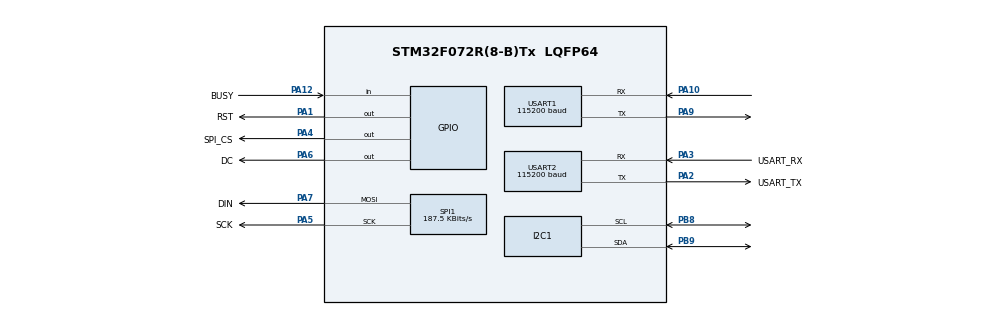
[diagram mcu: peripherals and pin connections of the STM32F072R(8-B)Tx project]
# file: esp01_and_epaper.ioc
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Dma.Request0=USART1_RX
Dma.USART1_RX.0.Direction=DMA_PERIPH_TO_MEMORY
Dma.USART1_RX.0.Instance=DMA1_Channel3
Dma.USART1_RX.0.MemDataAlignment=DMA_MDATAALIGN_BYTE
Dma.USART1_RX.0.MemInc=DMA_MINC_ENABLE
Dma.USART1_RX.0.Mode=DMA_CIRCULAR
Dma.USART1_RX.0.PeriphDataAlignment=DMA_PDATAALIGN_BYTE
Dma.USART1_RX.0.PeriphInc=DMA_PINC_DISABLE
Dma.USART1_RX.0.Priority=DMA_PRIORITY_LOW
I2C1.Timing=0x00201D2B
Mcu.Family=STM32F0
Mcu.Name=STM32F072R(8-B)Tx
Mcu.Package=LQFP64
NVIC.DMA1_Channel2_3_IRQn=true\:0\:0\:false\:false\:true\:false\:true\:true
NVIC.TIM3_IRQn=true\:0\:0\:false\:false\:true\:true\:true\:true
PA1.GPIO_Label=RST
PA1.Signal=GPIO_Output
PA10.Mode=Asynchronous
PA10.Signal=USART1_RX
PA12.GPIO_Label=BUSY
PA12.Signal=GPIO_Input
PA2.GPIO_Label=USART_TX
PA2.GPIO_Mode=GPIO_MODE_AF_PP
PA2.GPIO_PuPd=GPIO_NOPULL
PA2.GPIO_Speed=GPIO_SPEED_FREQ_LOW
PA2.Mode=Asynchronous
PA2.Signal=USART2_TX
PA3.GPIO_Label=USART_RX
PA3.GPIO_Mode=GPIO_MODE_AF_PP
PA3.GPIO_PuPd=GPIO_NOPULL
PA3.GPIO_Speed=GPIO_SPEED_FREQ_LOW
PA3.Mode=Asynchronous
PA3.Signal=USART2_RX
PA4.GPIO_Label=SPI_CS
PA4.Signal=GPIO_Output
PA5.GPIO_Label=SCK
PA5.Mode=TX_Only_Simplex_Unidirect_Master
PA5.Signal=SPI1_SCK
PA6.GPIO_Label=DC
PA6.Signal=GPIO_Output
PA7.GPIO_Label=DIN
PA7.Mode=TX_Only_Simplex_Unidirect_Master
PA7.Signal=SPI1_MOSI
PA9.Mode=Asynchronous
PA9.Signal=USART1_TX
PB8.GPIO_Pu=GPIO_PULLUP
PB8.Mode=I2C
PB8.Signal=I2C1_SCL
PB9.GPIO_Pu=GPIO_PULLUP
PB9.Mode=I2C
PB9.Signal=I2C1_SDA
ProjectManager.HeapSize=0x200
ProjectManager.StackSize=0x400
ProjectManager.TargetToolchain=STM32CubeIDE
RCC.AHBFreq_Value=48000000
RCC.APB1Freq_Value=48000000
RCC.APB1TimFreq_Value=48000000
RCC.FLatency-AdvancedSettings=FLASH_LATENCY_1
RCC.HCLKFreq_Value=48000000
RCC.PLLDivider=RCC_PREDIV_DIV2
RCC.PLLMUL=RCC_PLL_MUL12
RCC.PREFETCH_ENABLE-AdvancedSettings=1
RCC.SYSCLKFreq_VALUE=48000000
RCC.SYSCLKSource=RCC_SYSCLKSOURCE_HSI48
SPI1.BaudRatePrescaler=SPI_BAUDRATEPRESCALER_256
SPI1.CalculateBaudRate=187.5 KBits/s
SPI1.DataSize=SPI_DATASIZE_8BIT
SPI1.Direction=SPI_DIRECTION_2LINES
SPI1.Mode=SPI_MODE_MASTER
SPI1.VirtualType=VM_MASTER
TIM3.Period=59999
TIM3.Prescaler=47999
USART1.BaudRate=115200
USART1.VirtualMode-Asynchronous=VM_ASYNC
USART2.BaudRate=115200
USART2.VirtualMode=VM_ASYNC
USART2.VirtualMode-Asynchronous=VM_ASYNC
VP_TIM3_VS_ClockSourceINT.Mode=Internal
board=NUCLEO-F072RB

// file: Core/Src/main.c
/* USER CODE BEGIN Header */
/**
  ******************************************************************************
  * @file           : main.c
  * @brief          : Main program body
  ******************************************************************************
  * @attention
  *
  * Copyright (c) 2026 STMicroelectronics.
  * All rights reserved.
  *
  * This software is licensed under terms that can be found in the LICENSE file
  * in the root directory of this software component.
  * If no LICENSE file comes with this software, it is provided AS-IS.
  *
  ******************************************************************************
  */
/* USER CODE END Header */
#include "main.h"

/* USER CODE BEGIN Includes */

#include <stdio.h>
#include <stdlib.h> // malloc() free()
#include <string.h>
#include "ESP01_HAL.h"
#include "date_converter.h"
#include "DRIVER.h"
#include "EPAPER.h"
#include "bme280.h"

/* USER CODE END Includes */

I2C_HandleTypeDef hi2c1;

SPI_HandleTypeDef hspi1;

TIM_HandleTypeDef htim3;

UART_HandleTypeDef huart1;
UART_HandleTypeDef huart2;
DMA_HandleTypeDef hdma_usart1_rx;

/* USER CODE BEGIN PV */
uint8_t dma_rx_buf[1024]; // Buffer DMA pour la réception ESP01
/* USER CODE END PV */

void SystemClock_Config(void);
static void MX_GPIO_Init(void);
static void MX_DMA_Init(void);
static void MX_USART2_UART_Init(void);
static void MX_USART1_UART_Init(void);
static void MX_SPI1_Init(void);
static void MX_TIM3_Init(void);
static void MX_I2C1_Init(void);

/* USER CODE BEGIN 0 */
uint8_t day = 0;
uint8_t prev_day = 0;
uint8_t dd = 0;
uint8_t mm = 0;
uint16_t yy = 0;
uint16_t minute = 0;
uint16_t prev_minute = 0;
uint8_t moon_phase = 0;

int temp = 0;
int prev_temp = 0;
uint32_t press = 0;
uint32_t prev_press = 0;
uint32_t hum = 0;
uint32_t prev_hum = 0;

uint8_t wifi_update_done = 0;
/* USER CODE END 0 */

int main(void)
{

  /* MCU Configuration--------------------------------------------------------*/

  /* Reset of all peripherals, Initializes the Flash interface and the Systick. */
  HAL_Init();

  /* Configure the system clock */
  SystemClock_Config();

  /* Initialize all configured peripherals */
  MX_GPIO_Init();
  MX_DMA_Init();
  MX_USART2_UART_Init();
  MX_USART1_UART_Init();
  MX_SPI1_Init();
  MX_TIM3_Init();
  MX_I2C1_Init();
  /* USER CODE BEGIN 2 */

  if (HAL_TIM_Base_Start_IT(&htim3) != HAL_OK)
  {
    /* Starting Error */
    Error_Handler();
  }
  BME_Init();
  BME_Read_Data(&temp, &press, &hum);

  Init_Wifi("Wifi_name", "Wifi_pswd");
  if(Get_Date(&day, &dd, &mm, &yy, &minute) == 0){
	UTC_to_Paris(&day, &dd, &mm, &yy, &minute);
  }
  prev_minute = minute + 1111;

  moon_phase = Moon_Phase(dd,mm,yy);

  EPAPER_Init();
  EPAPER_Clear();
  HAL_Delay(500);
  EPAPER_Part_Init();
  EPAPER_KW_White_Display();
  HAL_Delay(500);

  EPAPER_Print_temp(temp);
  EPAPER_Print_press(press);
  EPAPER_Print_hum(hum);
  EPAPER_Print_Date(day,  dd, mm);
  EPAPER_Print_Hour(minute,  prev_minute);
  EPAPER_Print_Moon_Phase(moon_phase, minute, 360, 1080);

  prev_minute = minute;
  prev_day = day;
  prev_temp = temp;
  prev_hum = hum;
  prev_press = press;
  /* USER CODE END 2 */

  /* Infinite loop */
  /* USER CODE BEGIN WHILE */
  while (1)
  {

	if(prev_minute != minute)
	{
		if(minute >= 1440){
			minute = 0;
			day++;
		}

		EPAPER_Print_Hour(minute,  prev_minute);
		EPAPER_Print_Moon_Phase(moon_phase, minute, 360, 1080);
		prev_minute = minute;

		/* update temp hum and press each minute */
		BME_Read_Data(&temp, &press, &hum);

		if(prev_temp != temp){
			prev_temp = temp;
			EPAPER_Print_temp(temp);
		}
		if(prev_press != press){
			prev_press = press;
			EPAPER_Print_press(press);
		}
		if(prev_hum != hum){
			prev_hum = hum;
			EPAPER_Print_hum(hum);
		}
	}

	if(prev_day != day)
	{
		if(day >= 7){
			day = 0;
		}
		prev_day = day;

		next_day(&dd,&mm,&yy);

		EPAPER_Print_Date(day,  dd, mm);
		moon_phase = Moon_Phase(dd,mm,yy);
	}

	/* reset screen every day at 4h*/
	if((minute == 240 || minute == 600 || minute == 960 || minute == 1320) && !wifi_update_done){
		wifi_update_done = 1;

		Init_Wifi("Wifi_name", "Wifi_pswd");
		if(Get_Date(&day, &dd, &mm, &yy, &minute) == 0){
			UTC_to_Paris(&day, &dd, &mm, &yy, &minute);
		}
		prev_minute = minute + 1111;

		EPAPER_Init();
		EPAPER_Clear();
		HAL_Delay(500);
		EPAPER_Part_Init();
		EPAPER_KW_White_Display();
		HAL_Delay(500);

		EPAPER_Print_temp(temp);
		EPAPER_Print_press(press);
		EPAPER_Print_hum(hum);
		EPAPER_Print_Date(day,  dd, mm);
		EPAPER_Print_Hour(minute,  prev_minute);
		EPAPER_Print_Moon_Phase(moon_phase, minute, 360, 1080);
		prev_minute = minute;
		prev_day = day;
		prev_temp = temp;
		prev_hum = hum;
		prev_press = press;
	}

	if(minute == 241 || minute == 601 || minute == 961 || minute == 1321){
		wifi_update_done = 0;
	}
    /* USER CODE END WHILE */

  }
}

void SystemClock_Config(void)
{
  RCC_OscInitTypeDef RCC_OscInitStruct = {0};
  RCC_ClkInitTypeDef RCC_ClkInitStruct = {0};
  RCC_PeriphCLKInitTypeDef PeriphClkInit = {0};

  /** Initializes the RCC Oscillators according to the specified parameters
  * in the RCC_OscInitTypeDef structure.
  */
  RCC_OscInitStruct.OscillatorType = RCC_OSCILLATORTYPE_HSI|RCC_OSCILLATORTYPE_HSE;
  RCC_OscInitStruct.HSEState = RCC_HSE_ON;
  RCC_OscInitStruct.HSIState = RCC_HSI_ON;
  RCC_OscInitStruct.HSICalibrationValue = RCC_HSICALIBRATION_DEFAULT;
  RCC_OscInitStruct.PLL.PLLState = RCC_PLL_ON;
  RCC_OscInitStruct.PLL.PLLSource = RCC_PLLSOURCE_HSE;
  RCC_OscInitStruct.PLL.PLLMUL = RCC_PLL_MUL12;
  RCC_OscInitStruct.PLL.PREDIV = RCC_PREDIV_DIV2;
  if (HAL_RCC_OscConfig(&RCC_OscInitStruct) != HAL_OK)
  {
    Error_Handler();
  }

  /** Initializes the CPU, AHB and APB buses clocks
  */
  RCC_ClkInitStruct.ClockType = RCC_CLOCKTYPE_HCLK|RCC_CLOCKTYPE_SYSCLK
                              |RCC_CLOCKTYPE_PCLK1;
  RCC_ClkInitStruct.SYSCLKSource = RCC_SYSCLKSOURCE_PLLCLK;
  RCC_ClkInitStruct.AHBCLKDivider = RCC_SYSCLK_DIV1;
  RCC_ClkInitStruct.APB1CLKDivider = RCC_HCLK_DIV1;

  if (HAL_RCC_ClockConfig(&RCC_ClkInitStruct, FLASH_LATENCY_1) != HAL_OK)
  {
    Error_Handler();
  }
  PeriphClkInit.PeriphClockSelection = RCC_PERIPHCLK_USART1|RCC_PERIPHCLK_USART2
                              |RCC_PERIPHCLK_I2C1;
  PeriphClkInit.Usart1ClockSelection = RCC_USART1CLKSOURCE_PCLK1;
  PeriphClkInit.Usart2ClockSelection = RCC_USART2CLKSOURCE_PCLK1;
  PeriphClkInit.I2c1ClockSelection = RCC_I2C1CLKSOURCE_HSI;
  if (HAL_RCCEx_PeriphCLKConfig(&PeriphClkInit) != HAL_OK)
  {
    Error_Handler();
  }
}

static void MX_I2C1_Init(void)
{

  hi2c1.Instance = I2C1;
  hi2c1.Init.Timing = 0x00201D2B;
  hi2c1.Init.OwnAddress1 = 0;
  hi2c1.Init.AddressingMode = I2C_ADDRESSINGMODE_7BIT;
  hi2c1.Init.DualAddressMode = I2C_DUALADDRESS_DISABLE;
  hi2c1.Init.OwnAddress2 = 0;
  hi2c1.Init.OwnAddress2Masks = I2C_OA2_NOMASK;
  hi2c1.Init.GeneralCallMode = I2C_GENERALCALL_DISABLE;
  hi2c1.Init.NoStretchMode = I2C_NOSTRETCH_DISABLE;
  if (HAL_I2C_Init(&hi2c1) != HAL_OK)
  {
    Error_Handler();
  }

  /** Configure Analogue filter
  */
  if (HAL_I2CEx_ConfigAnalogFilter(&hi2c1, I2C_ANALOGFILTER_ENABLE) != HAL_OK)
  {
    Error_Handler();
  }

  /** Configure Digital filter
  */
  if (HAL_I2CEx_ConfigDigitalFilter(&hi2c1, 0) != HAL_OK)
  {
    Error_Handler();
  }

}

static void MX_SPI1_Init(void)
{

  /* SPI1 parameter configuration*/
  hspi1.Instance = SPI1;
  hspi1.Init.Mode = SPI_MODE_MASTER;
  hspi1.Init.Direction = SPI_DIRECTION_2LINES;
  hspi1.Init.DataSize = SPI_DATASIZE_8BIT;
  hspi1.Init.CLKPolarity = SPI_POLARITY_LOW;
  hspi1.Init.CLKPhase = SPI_PHASE_1EDGE;
  hspi1.Init.NSS = SPI_NSS_SOFT;
  hspi1.Init.BaudRatePrescaler = SPI_BAUDRATEPRESCALER_256;
  hspi1.Init.FirstBit = SPI_FIRSTBIT_MSB;
  hspi1.Init.TIMode = SPI_TIMODE_DISABLE;
  hspi1.Init.CRCCalculation = SPI_CRCCALCULATION_DISABLE;
  hspi1.Init.CRCPolynomial = 7;
  hspi1.Init.CRCLength = SPI_CRC_LENGTH_DATASIZE;
  hspi1.Init.NSSPMode = SPI_NSS_PULSE_ENABLE;
  if (HAL_SPI_Init(&hspi1) != HAL_OK)
  {
    Error_Handler();
  }

}

static void MX_TIM3_Init(void)
{

  TIM_ClockConfigTypeDef sClockSourceConfig = {0};
  TIM_MasterConfigTypeDef sMasterConfig = {0};

  htim3.Instance = TIM3;
  htim3.Init.Prescaler = 47999;
  htim3.Init.CounterMode = TIM_COUNTERMODE_UP;
  htim3.Init.Period = 59999;
  htim3.Init.ClockDivision = TIM_CLOCKDIVISION_DIV1;
  htim3.Init.AutoReloadPreload = TIM_AUTORELOAD_PRELOAD_DISABLE;
  if (HAL_TIM_Base_Init(&htim3) != HAL_OK)
  {
    Error_Handler();
  }
  sClockSourceConfig.ClockSource = TIM_CLOCKSOURCE_INTERNAL;
  if (HAL_TIM_ConfigClockSource(&htim3, &sClockSourceConfig) != HAL_OK)
  {
    Error_Handler();
  }
  sMasterConfig.MasterOutputTrigger = TIM_TRGO_RESET;
  sMasterConfig.MasterSlaveMode = TIM_MASTERSLAVEMODE_DISABLE;
  if (HAL_TIMEx_MasterConfigSynchronization(&htim3, &sMasterConfig) != HAL_OK)
  {
    Error_Handler();
  }

}

static void MX_USART1_UART_Init(void)
{

  huart1.Instance = USART1;
  huart1.Init.BaudRate = 115200;
  huart1.Init.WordLength = UART_WORDLENGTH_8B;
  huart1.Init.StopBits = UART_STOPBITS_1;
  huart1.Init.Parity = UART_PARITY_NONE;
  huart1.Init.Mode = UART_MODE_TX_RX;
  huart1.Init.HwFlowCtl = UART_HWCONTROL_NONE;
  huart1.Init.OverSampling = UART_OVERSAMPLING_16;
  huart1.Init.OneBitSampling = UART_ONE_BIT_SAMPLE_DISABLE;
  huart1.AdvancedInit.AdvFeatureInit = UART_ADVFEATURE_NO_INIT;
  if (HAL_UART_Init(&huart1) != HAL_OK)
  {
    Error_Handler();
  }

}

static void MX_USART2_UART_Init(void)
{

  huart2.Instance = USART2;
  huart2.Init.BaudRate = 115200;
  huart2.Init.WordLength = UART_WORDLENGTH_8B;
  huart2.Init.StopBits = UART_STOPBITS_1;
  huart2.Init.Parity = UART_PARITY_NONE;
  huart2.Init.Mode = UART_MODE_TX_RX;
  huart2.Init.HwFlowCtl = UART_HWCONTROL_NONE;
  huart2.Init.OverSampling = UART_OVERSAMPLING_16;
  huart2.Init.OneBitSampling = UART_ONE_BIT_SAMPLE_DISABLE;
  huart2.AdvancedInit.AdvFeatureInit = UART_ADVFEATURE_NO_INIT;
  if (HAL_UART_Init(&huart2) != HAL_OK)
  {
    Error_Handler();
  }

}

static void MX_DMA_Init(void)
{

  /* DMA controller clock enable */
  __HAL_RCC_DMA1_CLK_ENABLE();

  /* DMA interrupt init */
  /* DMA1_Channel2_3_IRQn interrupt configuration */
  HAL_NVIC_SetPriority(DMA1_Channel2_3_IRQn, 0, 0);
  HAL_NVIC_EnableIRQ(DMA1_Channel2_3_IRQn);

}

static void MX_GPIO_Init(void)
{
  GPIO_InitTypeDef GPIO_InitStruct = {0};

  /* GPIO Ports Clock Enable */
  __HAL_RCC_GPIOF_CLK_ENABLE();
  __HAL_RCC_GPIOA_CLK_ENABLE();
  __HAL_RCC_GPIOB_CLK_ENABLE();

  /*Configure GPIO pin Output Level */
  HAL_GPIO_WritePin(GPIOA, RST_Pin|SPI_CS_Pin|DC_Pin, GPIO_PIN_RESET);

  /*Configure GPIO pin : BUSY_Pin */
  GPIO_InitStruct.Pin = BUSY_Pin;
  GPIO_InitStruct.Mode = GPIO_MODE_INPUT;
  GPIO_InitStruct.Pull = GPIO_NOPULL;
  HAL_GPIO_Init(BUSY_GPIO_Port, &GPIO_InitStruct);

  /*Configure GPIO pins : RST_Pin SPI_CS_Pin DC_Pin */
  GPIO_InitStruct.Pin = RST_Pin|SPI_CS_Pin|DC_Pin;
  GPIO_InitStruct.Mode = GPIO_MODE_OUTPUT_PP;
  GPIO_InitStruct.Pull = GPIO_NOPULL;
  GPIO_InitStruct.Speed = GPIO_SPEED_FREQ_LOW;
  HAL_GPIO_Init(GPIOA, &GPIO_InitStruct);

}

void Error_Handler(void)
{
  __disable_irq();
  while (1)
  {
  }
}
